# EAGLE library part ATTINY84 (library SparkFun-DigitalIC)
Atmel 14-pin 2/4/8kB flash uC

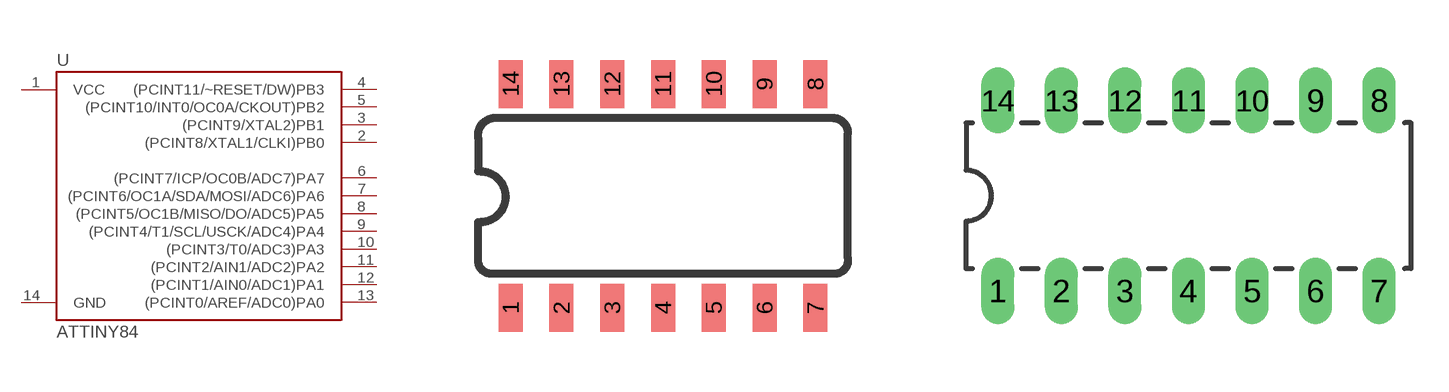
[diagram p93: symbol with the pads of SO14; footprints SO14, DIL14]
Designator prefix -

## ATTINY84  [SO14]
1  VCC
2  (PCINT8/XTAL1/CLKI)PB0
3  (PCINT9/XTAL2)PB1
4  (PCINT11/~RESET/DW)PB3
5  (PCINT10/INT0/OC0A/CKOUT)PB2
6  (PCINT7/ICP/OC0B/ADC7)PA7
7  (PCINT6/OC1A/SDA/MOSI/ADC6)PA6
8  (PCINT5/OC1B/MISO/DO/ADC5)PA5
9  (PCINT4/T1/SCL/USCK/ADC4)PA4
10  (PCINT3/T0/ADC3)PA3
11  (PCINT2/AIN1/ADC2)PA2
12  (PCINT1/AIN0/ADC1)PA1
13  (PCINT0/AREF/ADC0)PA0
14  GND

## ATTINY84ATTINY84-20PU  [DIL14]
Pads as for SO14

## Footprint SO14 (pad centres in mm)
smd 0.6 x 1.2: 1 -3.81,-2.8; 2 -2.54,-2.8; 3 -1.27,-2.8; 4 0,-2.8; 5 1.27,-2.8; 6 2.54,-2.8; 7 3.81,-2.8; 8 3.81,2.8; 9 2.54,2.8; 10 1.27,2.8; 11 0,2.8; 12 -1.27,2.8; 13 -2.54,2.8; 14 -3.81,2.8

## Footprint DIL14 (pad centres in mm)
drill 0.813 long: 1 -8.89,-3.81; 2 -6.35,-3.81; 3 -3.81,-3.81; 4 -1.27,-3.81; 5 1.27,-3.81; 6 3.81,-3.81; 7 6.35,-3.81; 8 6.35,3.81; 9 3.81,3.81; 10 1.27,3.81; 11 -1.27,3.81; 12 -3.81,3.81; 13 -6.35,3.81; 14 -8.89,3.81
